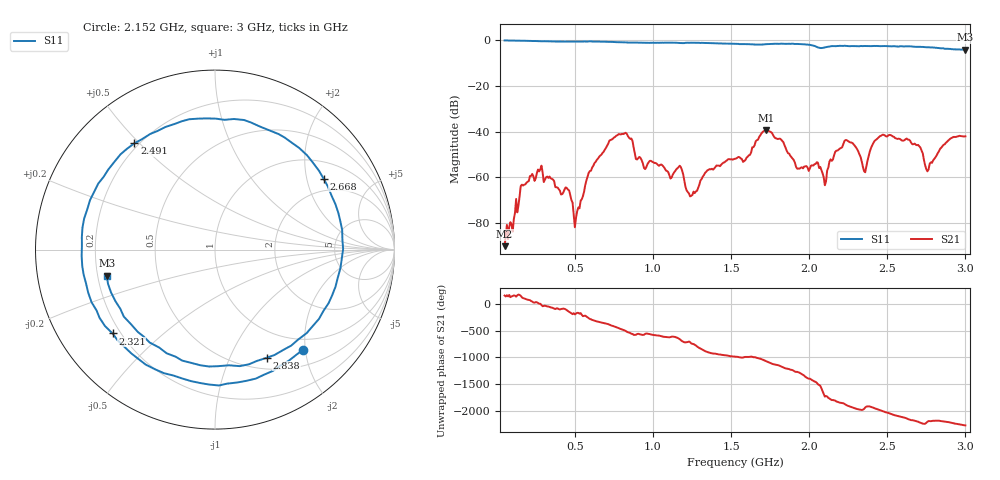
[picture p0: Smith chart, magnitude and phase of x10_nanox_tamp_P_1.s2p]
! nanovna_capture.py 2026-10-18T20:56:27+0900
! NanoVNA-F_V2 fw 0.6.0 SN 4A3639384505514B
! cal: load open short thru cal'ed  over 50000000-3000000000 Hz, 201 points
! points 401, avg 4
! S21: port1 = green ~10 mm H loop (flat, tape), port2 = GSM antenna; modified (implanted) Nano X at position P (P = user-found best placement), placement 1
# HZ S RI R 50
! S12 and S22 are not measured (written as 0)
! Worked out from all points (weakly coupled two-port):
!   401 points, 50 MHz to 3 GHz, reference 50 ohm
!   highest |S21| = -39.48 dB at 1.724 GHz (marker M1); lowest = -90.2 dB at 50 MHz (marker M2)
!   lowest |S11| = -4.1 dB at 3 GHz (marker M3), VSWR 4.27, Z = 11.9 - j5.59 ohm
!   |S11| at or under -10 dB: nowhere
!   S12 and S22 are empty: the file has one direction only
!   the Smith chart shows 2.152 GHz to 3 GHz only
!   S11 on the Smith chart (normalised r, x): 2.152 GHz: 0.79, -1.95; 2.321 GHz: 0.17, -0.35; 2.491 GHz: 0.18, +0.48; 2.668 GHz: 1.53, +2.53; 2.838 GHz: 0.64, -1.39; 3 GHz: 0.24, -0.11
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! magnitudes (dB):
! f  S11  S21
! 50 MHz  -0.1  -90.2
! 271.2 MHz  -0.4  -57.4
! 507.2 MHz  -0.6  -77.7
! 544.1 MHz  -0.6  -69.6
! 772.8 MHz  -0.9  -41.6
! 1.038 GHz  -1.1  -55.0
! 1.171 GHz  -1.2  -54.9
! 1.252 GHz  -1.1  -67.8
! 1.525 GHz  -1.6  -51.9
! 1.724 GHz  -1.7  -39.5
! 2.019 GHz  -2.2  -54.8
! 2.1 GHz  -3.1  -63.5
! 2.152 GHz  -2.6  -52.2
! 2.24 GHz  -2.5  -43.7
! 2.321 GHz  -2.6  -50.0
! 2.358 GHz  -2.5  -57.8
! 2.491 GHz  -2.6  -42.1
! 2.513 GHz  -2.7  -41.4
! 2.668 GHz  -2.8  -45.5
! 2.757 GHz  -3.1  -57.4
! 2.838 GHz  -3.5  -47.6
! 3 GHz  -4.1  -42.1
